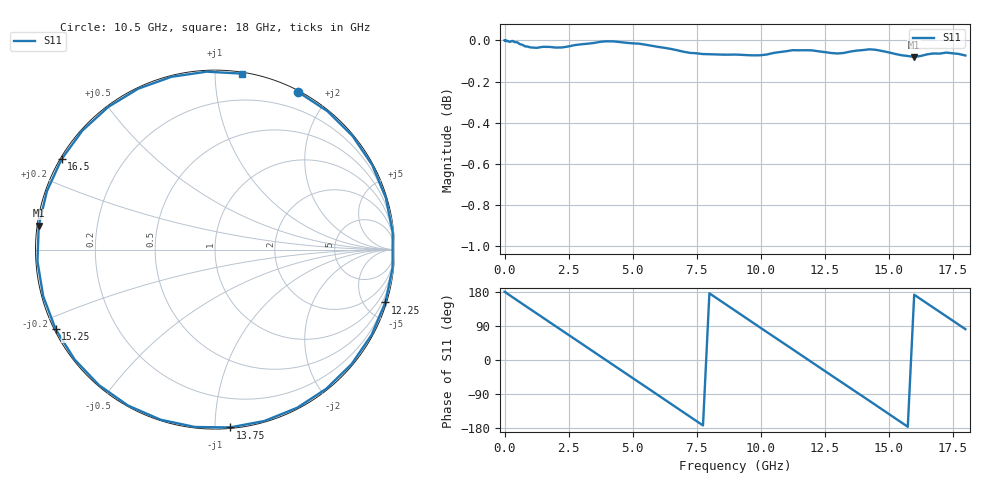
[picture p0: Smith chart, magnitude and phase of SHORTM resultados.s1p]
#	HZ	S	MA	R	50.00
! Rohde & Schwarz Vector Network Analyzer
! Rohde-Schwarz,ZNB43-2Port,1334333092101683,4.21
! Created: UTC 09/15/2026, 11:47:42 AM
! freq[Hz]	mag:S12	ang:S12
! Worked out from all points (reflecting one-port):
!   116 points, 9 kHz to 18 GHz, reference 50 ohm
!   lowest |S11| = -0.1 dB at 16 GHz (marker M1), VSWR 216.54, Z = 0.232 + j3.37 ohm
!   phase of S11 starts at 180 deg and turns -819 deg over the sweep
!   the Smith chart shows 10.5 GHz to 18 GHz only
!   S11 on the Smith chart (normalised r, x): 10.5 GHz: 0.01, +1.66; 12.25 GHz: 0.13, -6.60; 13.75 GHz: 0.01, -1.09; 15.25 GHz: 0.00, -0.24; 16.5 GHz: 0.00, +0.27; 18 GHz: 0.01, +1.16
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9000  1 180.0
6e8  0.9979 152.5
1.25e9  0.9959 122.9
1.75e9  0.9964 100.2
2.5e9  0.9967 66.2
3.25e9  0.9982 32.1
3.75e9  0.9993 9.3
4.25e9  0.9995 -13.4
4.75e9  0.9987 -36.1
5.5e9  0.9976 -70.2
6e9  0.9964 -92.9
7e9  0.9937 -138.6
7.5e9  0.9929 -161.3
8e9  0.9923 176.0
8.5e9  0.9921 153.2
9.25e9  0.992 119.1
9.75e9  0.9917 96.3
1.05e10  0.993 62.2
1.15e10  0.9945 16.8
1.225e10  0.994 -17.2
1.3e10  0.9927 -51.3
1.375e10  0.9943 -85.2
1.45e10  0.9948 -119.1
1.525e10  0.9925 -153.5
1.6e10  0.9908 172.3
1.65e10  0.9923 149.5
1.725e10  0.9932 115.5
1.8e10  0.9916 81.4
